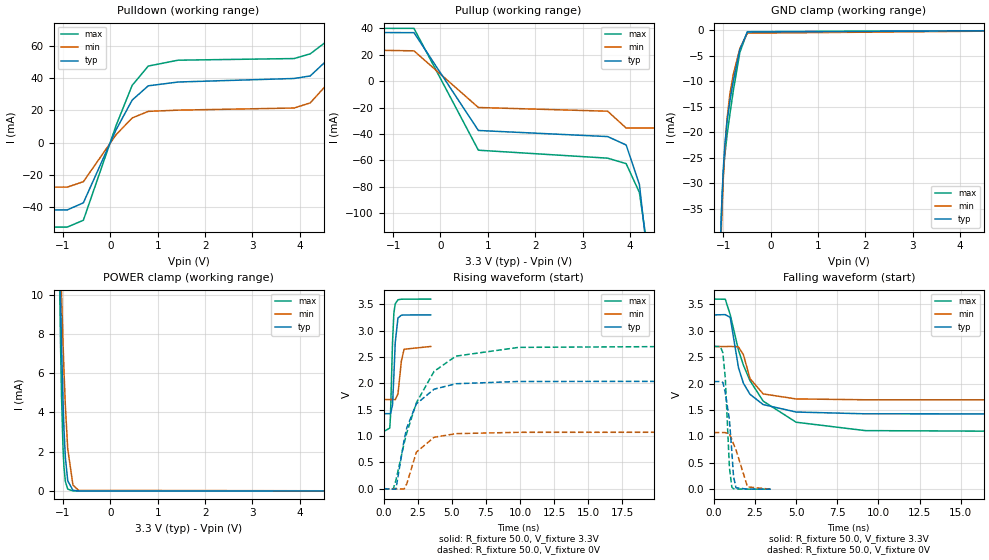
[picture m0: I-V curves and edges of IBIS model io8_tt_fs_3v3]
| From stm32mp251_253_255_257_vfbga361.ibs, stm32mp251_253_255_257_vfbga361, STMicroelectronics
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[Model]   io8_tt_fs_3v3
Model_type I/O
Polarity   Non-Inverting
Enable   Active-Low
| CAP_THRESHOLD on pad IOTT is "UDTCAPC" :
| Rising=30.0% of vddiov33m   Falling=70.0% of vddiov33m
| C_comp min and max val. don't necessarily correlate with the min and max pvt
| but are the smallest and greatest pad capacitance found.
| var   typ   min   max
C_comp   1.24003pF  995.41445fF  2.17631pF
|C_comp_pullup   730.17000fF  473.44500fF  1.67079pF
|C_comp_pulldown   509.85500fF  521.96945fF  505.52500fF
Vinl = 810.0mV
Vinh = 2.52V
Vmeas = 1.65V   | Reference voltage for timing measurements
Cref  = 50.0pF   | Timing specification test load capacitance value
Rref  = 100.0MOhm   | Timing specification test load resistance value
Vref  = 1.65V   | Timing specification test load voltage
[Model Spec]
| TIME_THRESHOLD on pin ZIV08M is "CMOS" :
| Rising=50.0% of vddv08m   Falling=50.0% of vddv08m
Vinl 1.08570V 868.70000mV 1.21270V
Vinh 1.55630V 1.26330V 1.71030V
| variable   typ   min   max
[Temperature Range] 25.0 125.0 -40.0
| variable   typ   min   max
[Voltage Range] 3.3V 2.7V 3.6V
| variable   typ   min   max
[POWER Clamp Reference] 3.3V 2.7V 3.6V
| variable   typ   min   max
[GND Clamp Reference] 0V 0V 0V
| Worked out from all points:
|   slope of the pulldown table from 0 to 0.495 V, typ, clamps not added: 18.2 ohm
|   slope of the pullup table from 0 to 0.495 V, typ, clamps not added: 17.3 ohm
|   GND clamp passes 1 mA (typ) near -0.55 V on its own axis
|   POWER clamp passes 1 mA (typ) near -0.93 V on its own axis
|   rising waveform, R_fixture 50.0, V_fixture 3.3V: 20-80 % time 193ps typ, 246ps min, 174ps max; typ from 1.43 V to 3.3 V
|   falling waveform, R_fixture 50.0, V_fixture 3.3V: 20-80 % time 982ps typ, 725ps min, 2.11ns max; typ from 3.3 V to 1.43 V
|   rising waveform, R_fixture 50.0, V_fixture 0V: 20-80 % time 1.26ns typ, 1.05ns min, 2.28ns max; typ from 0 V to 2.04 V
|   falling waveform, R_fixture 50.0, V_fixture 0V: 20-80 % time 361ps typ, 633ps min, 243ps max; typ from 2.04 V to 0 V
[POWER Clamp]
-3.3V     1.352A     318.4mA    1.997A
-1.07V    12.07mA    13.62mA    10.38mA
-1.06V    10.79mA    12.67mA    8.742mA
-1.05V    9.57mA     11.75mA    7.25mA
-1.03V    7.34mA     9.996mA    4.745mA
-1V       4.587mA    7.593mA    2.212mA
-980mV    3.182mA    6.169mA    1.235mA
-950mV    1.703mA    4.334mA    479uA
-900mV    514.7uA    2.139mA    90.77uA
-790mV    28.73uA    299.9uA    2.711uA
-670mV    1.278uA    27.54uA    387.5nA
6.6V      0A         0A         0A
[GND Clamp]
-3.3V     -3.764A    -3.734A    -3.781A
-1.05V    -39.76mA   -42.44mA   -39.2mA
-1.04V    -36.65mA   -39.24mA   -36.3mA
-1.03V    -33.91mA   -36.36mA   -33.82mA
-1V       -27.43mA   -29.21mA   -28.35mA
-970mV    -22.87mA   -23.78mA   -24.78mA
-920mV    -17.9mA    -17.36mA   -20.6mA
-860mV    -13.88mA   -12.47mA   -16.46mA
-790mV    -10.04mA   -8.727mA   -11.99mA
-650mV    -3.744mA   -3.565mA   -4.327mA
-490mV    -324.2uA   -555.2uA   -259.7uA
6.6V      204.7nA    4.775uA    218.9nA
| variable   typ   min   max
[Pullup Reference] 3.3V 2.7V 3.6V
| variable   typ   min   max
[Pulldown Reference] 0V 0V 0V
[Pullup]
-3.3V     37.13mA    24.46mA    39.98mA
-560mV    36.73mA    22.97mA    39.98mA
800mV     -37.34mA   -19.93mA   -52.27mA
3.53V     -41.95mA   -22.74mA   -58.3mA
3.92V     -48.32mA   -35.5mA    -62.45mA
4.2V      -78.22mA   -35.5mA    -84.3mA
4.4V      -143mA     -35.5mA    -133.8mA
4.46V     -171mA     -35.5mA    -160.6mA
4.55V     -171.9mA   -35.5mA    -215.7mA
4.71V     -171.9mA   -35.5mA    -363.1mA
4.74V     -171.9mA   -35.5mA    -377.8mA
6.6V      -171.9mA   -35.5mA    -377.9mA
[Pulldown]
-3.3V     -41.64mA   -27.52mA   -52.25mA
-910mV    -41.63mA   -27.52mA   -52.25mA
-570mV    -37.25mA   -24.18mA   -48.03mA
120mV     7.91mA     4.861mA    10.53mA
460mV     26.3mA     15.25mA    35.41mA
800mV     35.13mA    19.32mA    47.35mA
1.43V     37.49mA    20.09mA    50.99mA
3.88V     39.67mA    21.4mA     52mA
4.22V     41.24mA    24.57mA    54.92mA
4.56V     50.57mA    35.57mA    62.45mA
4.9V      81.48mA    69.85mA    90.32mA
6.6V      933.2mA    945.7mA    873mA
[Ramp]
dV/dt_r 1.22272V/1.2588ns 642.93702mV/1.04649ns 1.62249V/2.27905ns
dV/dt_f 1.12486V/980.80926ps 604.29684mV/718.98041ps 1.50796V/2.11138ns
R_load = 50.0
| Removed startup time: 0s 0s 0s  .
| Removed end time: 3.45ns.
[Rising Waveform]
R_fixture   = 50.0
V_fixture   = 3.3V
V_fixture_min = 2.7V
V_fixture_max = 3.6V
0s        1.425V     1.693V     1.087V
450ps     1.425V     1.693V     1.151V
500ps     1.424V     1.693V     1.375V
650ps     1.587V     1.693V     2.771V
750ps     2.148V     1.693V     3.336V
850ps     2.774V     1.689V     3.511V
1.05ns    3.241V     1.8V       3.587V
1.3ns     3.294V     2.425V     3.597V
1.5ns     3.298V     2.648V     3.598V
3.45ns    3.3V       2.7V       3.6V
| Removed startup time: 0s 0s 0s  .
| Removed end time: 24.9ns.
[Falling Waveform]
R_fixture   = 50.0
V_fixture   = 3.3V
V_fixture_min = 2.7V
V_fixture_max = 3.6V
0s        3.3V       2.7V       3.6V
700ps     3.305V     2.7V       3.596V
1ns       3.253V     2.704V     3.302V
1.5ns     2.301V     2.694V     2.633V
1.8ns     2.006V     2.546V     2.348V
2.2ns     1.797V     2.094V     2.055V
3ns       1.602V     1.804V     1.668V
5ns       1.461V     1.709V     1.268V
9.2ns     1.427V     1.693V     1.109V
24.9ns    1.425V     1.693V     1.087V
| Removed startup time: 0s 0s 0s  .
| Removed end time: 24.9ns.
[Rising Waveform]
R_fixture   = 50.0
V_fixture   = 0V
V_fixture_min = 0V
V_fixture_max = 0V
0s        357.9nV    2.102uV    437.2nV
700ps     -7.984mV   -107.9uV   -7.446mV
900ps     -7.58mV    -1.784mV   160.4mV
1.5ns     923.1mV    -4.901mV   859.9mV
1.7ns     1.16V      95.78mV    1.064V
2.4ns     1.611V     695mV      1.632V
3.7ns     1.89V      977.2mV    2.228V
5.3ns     1.993V     1.046V     2.517V
9.9ns     2.036V     1.071V     2.683V
24.9ns    2.038V     1.072V     2.704V
| Removed startup time: 0s 0s 0s  .
| Removed end time: 3.45ns.
[Falling Waveform]
R_fixture   = 50.0
V_fixture   = 0V
V_fixture_min = 0V
V_fixture_max = 0V
0s        2.038V     1.072V     2.704V
400ps     2.038V     1.072V     2.702V
550ps     2.022V     1.072V     2.585V
700ps     1.829V     1.072V     2.102V
950ps     1.312V     1.043V     412.3mV
1.1ns     696.7mV    941.8mV    33.79mV
1.2ns     238.6mV    855.6mV    9.036mV
1.35ns    26.73mV    744.5mV    3.299mV
2.05ns    825.1uV    42.45mV    837uV
3.45ns    217.6uV    280.5uV    245.1uV
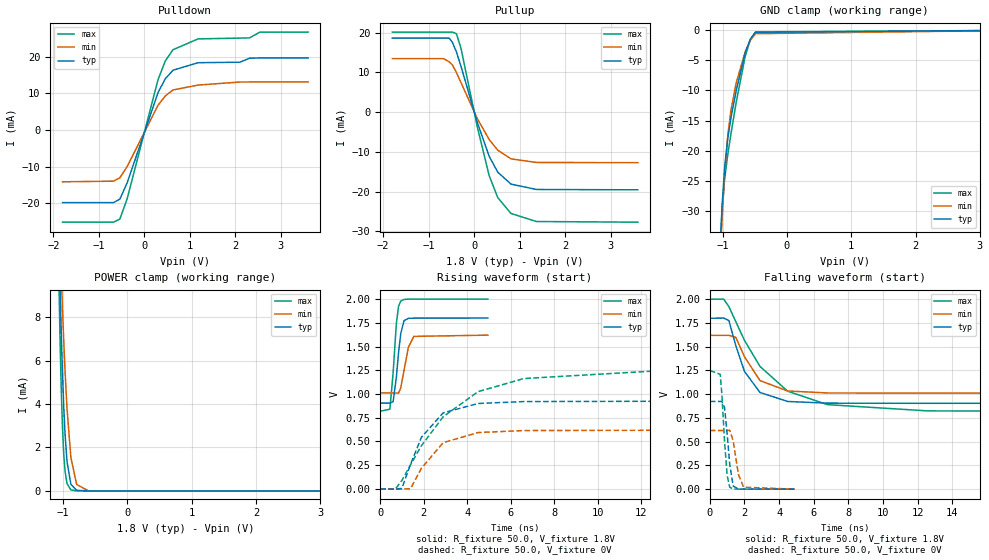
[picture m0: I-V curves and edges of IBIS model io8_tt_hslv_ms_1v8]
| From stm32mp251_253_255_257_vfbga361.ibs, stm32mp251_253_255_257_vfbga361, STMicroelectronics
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[Model]   io8_tt_hslv_ms_1v8
Model_type I/O
Polarity   Non-Inverting
Enable   Active-Low
| CAP_THRESHOLD on pad IOTT is "UDTCAPC" :
| Rising=30.0% of vddiov33m   Falling=70.0% of vddiov33m
| C_comp min and max val. don't necessarily correlate with the min and max pvt
| but are the smallest and greatest pad capacitance found.
| var   typ   min   max
C_comp   1.16081pF  1.09790pF  1.36391pF
|C_comp_pullup   764.88000fF  538.03000fF  521.00000fF
|C_comp_pulldown   395.93200fF  559.87040fF  842.91418fF
Vinl = 486.0mV
Vinh = 1.4V
Vmeas = 900.0mV   | Reference voltage for timing measurements
Cref  = 50.0pF   | Timing specification test load capacitance value
Rref  = 100.0MOhm   | Timing specification test load resistance value
Vref  = 900.0mV   | Timing specification test load voltage
[Model Spec]
| TIME_THRESHOLD on pin ZIV08M is "CMOS" :
| Rising=50.0% of vddv08m   Falling=50.0% of vddv08m
Vinl 675.70000mV 623.70000mV 735.70000mV
Vinh 1.12730V 1.01130V 1.24930V
| variable   typ   min   max
[Temperature Range] 25.0 125.0 -40.0
| variable   typ   min   max
[Voltage Range] 1.8V 1.62V 2.0V
| variable   typ   min   max
[POWER Clamp Reference] 1.8V 1.62V 2.0V
| variable   typ   min   max
[GND Clamp Reference] 0V 0V 0V
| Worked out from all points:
|   slope of the pulldown table from 0 to 0.27 V, typ, clamps not added: 28.9 ohm
|   slope of the pullup table from 0 to 0.27 V, typ, clamps not added: 28.7 ohm
|   GND clamp passes 1 mA (typ) near -0.55 V on its own axis
|   POWER clamp passes 1 mA (typ) near -0.93 V on its own axis
|   rising waveform, R_fixture 50.0, V_fixture 1.8V: 20-80 % time 235ps typ, 297ps min, 208ps max; typ from 0.904 V to 1.8 V
|   falling waveform, R_fixture 50.0, V_fixture 1.8V: 20-80 % time 1.16ns typ, 1.2ns min, 2.78ns max; typ from 1.8 V to 0.904 V
|   rising waveform, R_fixture 50.0, V_fixture 0V: 20-80 % time 1.23ns typ, 1.26ns min, 2.88ns max; typ from 0 V to 0.923 V
|   falling waveform, R_fixture 50.0, V_fixture 0V: 20-80 % time 270ps typ, 327ps min, 250ps max; typ from 0.923 V to 0 V
[POWER Clamp]
-1.8V     152.1mA    105.6mA    221.1mA
-1.07V    12.07mA    13.61mA    10.38mA
-1.05V    9.569mA    11.75mA    7.248mA
-1.03V    7.339mA    9.993mA    4.743mA
-1.01V    5.42mA     8.358mA    2.898mA
-990mV    3.841mA    6.859mA    1.662mA
-970mV    2.609mA    5.513mA    906.4uA
-940mV    1.358mA    3.806mA    344.1uA
-880mV    308.2uA    1.548mA    45.5uA
-790mV    28.46uA    298.9uA    2.106uA
-610mV    213nA      7.572uA    9.541nA
3.6V      0A         0A         0A
[GND Clamp]
-1.8V     -1.214A    -1.184A    -1.231A
-1.05V    -39.75mA   -42.57mA   -39.2mA
-1.04V    -36.64mA   -39.37mA   -36.3mA
-1.01V    -29.33mA   -31.48mA   -29.9mA
-970mV    -22.87mA   -23.87mA   -24.77mA
-920mV    -17.89mA   -17.43mA   -20.6mA
-870mV    -14.47mA   -13.19mA   -17.12mA
-790mV    -10.04mA   -8.766mA   -11.99mA
-650mV    -3.743mA   -3.579mA   -4.327mA
-570mV    -1.451mA   -1.665mA   -1.53mA
-490mV    -324.1uA   -556uA     -259.6uA
3.6V      61.92nA    2.591uA    17.99nA
| variable   typ   min   max
[Pullup Reference] 1.8V 1.62V 2.0V
| variable   typ   min   max
[Pulldown Reference] 0V 0V 0V
[Pullup]
-1.8V     18.62mA    13.47mA    20.14mA
-670mV    18.62mA    13.46mA    20.14mA
-550mV    18.62mA    12.65mA    20.14mA
-480mV    17.57mA    11.91mA    20.14mA
-390mV    15.13mA    9.968mA    19.73mA
-290mV    11.53mA    7.43mA     16.05mA
70mV      -2.634mA   -1.643mA   -3.782mA
330mV     -11.11mA   -6.899mA   -16mA
520mV     -15.13mA   -9.584mA   -21.53mA
810mV     -18.11mA   -11.75mA   -25.5mA
1.37V     -19.46mA   -12.66mA   -27.52mA
3.6V      -19.55mA   -12.72mA   -27.69mA
[Pulldown]
-1.8V     -19.85mA   -14.16mA   -25.2mA
-680mV    -19.85mA   -13.99mA   -25.2mA
-540mV    -18.89mA   -13.07mA   -24.35mA
-380mV    -14.47mA   -9.996mA   -18.83mA
300mV     10.22mA    6.776mA    13.77mA
460mV     14.01mA    9.309mA    18.88mA
630mV     16.33mA    10.94mA    21.94mA
1.18V     18.38mA    12.27mA    24.89mA
2.1V      18.52mA    13.1mA     25.11mA
2.31V     19.61mA    13.12mA    25.16mA
2.54V     19.69mA    13.12mA    26.75mA
3.6V      19.69mA    13.12mA    26.75mA
[Ramp]
dV/dt_r 554.12503mV/1.23304ns 370.8282mV/1.25449ns 749.30232mV/2.87847ns
dV/dt_f 537.60497mV/1.15739ns 365.36351mV/1.19511ns 709.24847mV/2.78118ns
R_load = 50.0
| Removed startup time: 0s 0s 0s  .
| Removed end time: 4.95ns.
[Rising Waveform]
R_fixture   = 50.0
V_fixture   = 1.8V
V_fixture_min = 1.62V
V_fixture_max = 2.0V
0s        904.2mV    1.011V     818.1mV
450ps     904.2mV    1.011V     840.2mV
600ps     918.9mV    1.011V     1.221V
750ps     1.178V     1.011V     1.746V
850ps     1.437V     1.009V     1.924V
950ps     1.635V     1.064V     1.979V
1.1ns     1.772V     1.248V     1.996V
1.3ns     1.797V     1.491V     1.999V
1.55ns    1.799V     1.607V     1.999V
4.95ns    1.8V       1.62V      2V
| Removed startup time: 0s 0s 0s  .
| Removed end time: 34.9ns.
[Falling Waveform]
R_fixture   = 50.0
V_fixture   = 1.8V
V_fixture_min = 1.62V
V_fixture_max = 2.0V
0s        1.8V       1.62V      2V
800ps     1.802V     1.62V      2.002V
1.1ns     1.776V     1.62V      1.923V
1.5ns     1.513V     1.599V     1.764V
2ns       1.24V      1.395V     1.568V
2.9ns     1.018V     1.143V     1.292V
4.5ns     923.4mV    1.034V     1.031V
6.8ns     905.9mV    1.013V     890.1mV
12.6ns    904.2mV    1.011V     824.1mV
34.9ns    904.2mV    1.011V     818.1mV
| Removed startup time: 0s 0s 0s  .
| Removed end time: 34.8ns.
[Rising Waveform]
R_fixture   = 50.0
V_fixture   = 0V
V_fixture_min = 0V
V_fixture_max = 0V
0s        0V         0V         0V
700ps     -2.205mV   -8.125uV   -1.669mV
1ns       5.76mV     -1.507mV   88.81mV
1.4ns     259.6mV    3.003mV    254.5mV
1.9ns     544.7mV    218.3mV    455.8mV
2.9ns     801.7mV    488.1mV    760.9mV
4.5ns     900.3mV    594.2mV    1.025V
6.6ns     920.4mV    615.1mV    1.163V
12.5ns    923.4mV    617.9mV    1.241V
34.8ns    923.4mV    617.9mV    1.249V
| Removed startup time: 0s 0s 0s  .
| Removed end time: 4.9ns.
[Falling Waveform]
R_fixture   = 50.0
V_fixture   = 0V
V_fixture_min = 0V
V_fixture_max = 0V
0s        923.4mV    617.9mV    1.249V
600ps     923.4mV    617.9mV    1.21V
700ps     923.5mV    618mV      991.4mV
850ps     860.2mV    618mV      506.1mV
1ns       586.5mV    617.8mV    145.9mV
1.15ns    261.3mV    620.5mV    20.52mV
1.35ns    32.49mV    508.3mV    2.469mV
1.65ns    1.687mV    155.2mV    851uV
1.95ns    754.2uV    21.06mV    473.5uV
4.9ns     0V         0V         0V
